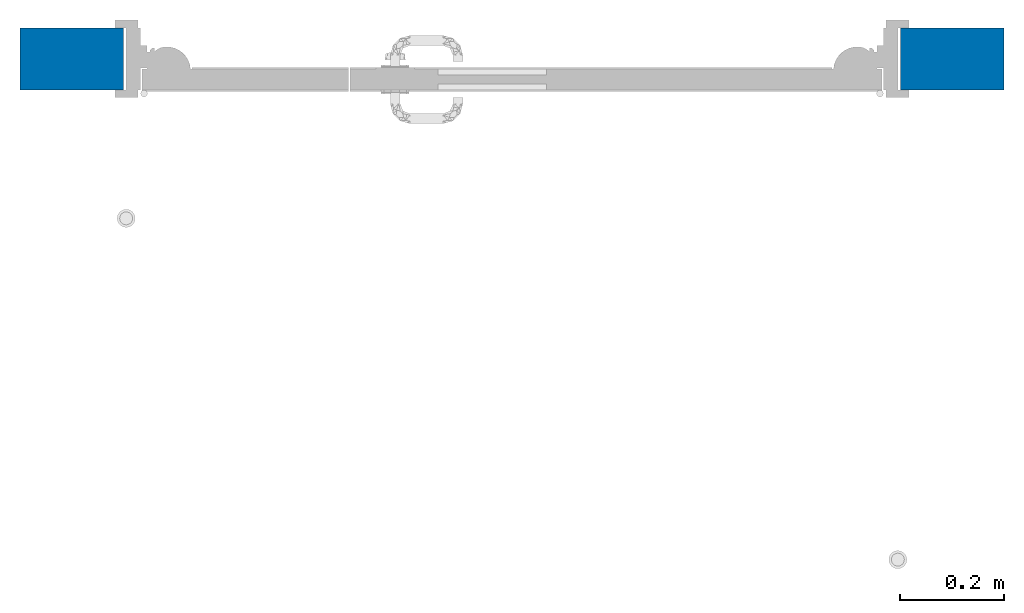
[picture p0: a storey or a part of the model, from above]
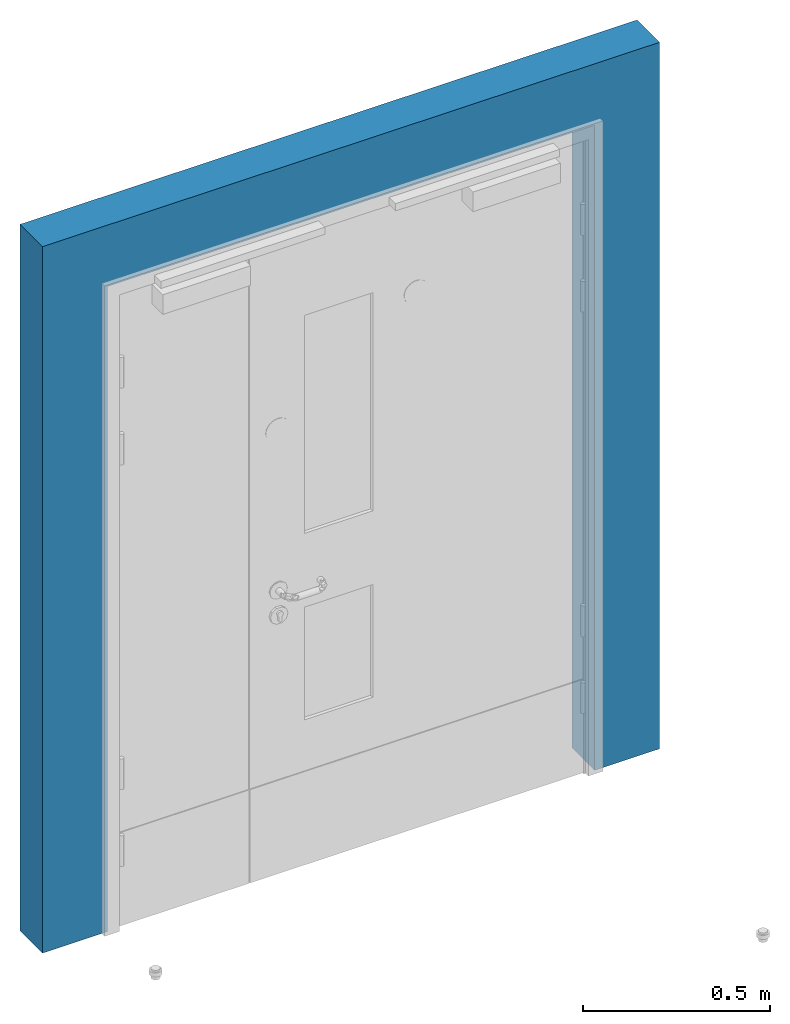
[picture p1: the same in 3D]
Properties of the parts of a building model (IFC2X3)

# File
Description: ViewDefinition [CoordinationView_V2.0]
File name: Project Number
Time: 2014-12-09T13:17:30
Written by: The EXPRESS Data Manager Version 5.01.0100.02.64mod : 6 Jun 2012
Made in: 20130709_2115(x64) - Exporter 3.12.0.0 - Alternate UI 2.12.0.0
Comment: STEP Physical File produced by: The EXPRESS Data Manager Version 5.01.0100.02.64mod : 6 Jun 2012 * Module: EDMstepFileFactory/EDMstandAlone * Creation date: Tue Dec 09 13:17:30 2014 * Host: NCL-PI08 * Database: C:\Users\KovacsG\AppData\Local\Temp\{1421A383-5437-4BC6-9070-A04BE4EB1C63}\ifc * Database version: 5507 * Database creation date: Tue Dec 09 13:17:29 2014 * Schema: IFC2X3 * Model: DataRepository.ifc * Model creation date: Tue Dec 09 13:17:29 2014 * Header model: DataRepository.ifc_HeaderModel * Header model creation date: Tue Dec 09 13:17:29 2014 * EDMuser: sdai-user * EDMgroup: sdai-group * License ID and type: 5605 : Permanent license. Expiry date: * EDMstepFileFactory options: 020000

# IfcProject, Project Number
LongName: Project Name; Phase: Project Status

# IfcSite, Default
RefLatitude: 51, 30, 0, 549316; RefLongitude: 0, -7, -34, -450321; RefElevation: 0 mm

# IfcBuildingStorey, Level 0
LongName: Level 0; Elevation: 0 mm

# IfcDoor: 1500x2100mm, NBS_AssaAbloyLtd_DrsetSym_MedicaSelectUnequalPair:1500x2100mm:411227
In: Level 0
Type - ParameterTakesPrecedence: no; Sizeable: no; Material: NBS_Concept, NBS_Glass
OverallHeight: 2100 mm; OverallWidth: 1500 mm
NBS_General - Author: NBS; BIMObjectName: NBS_AssaAbloyLtd_DoorsetSystem_MedicaSelectUnequalPair_1500x2100mm; ManufacturerURL: www.assaabloy.co.uk; NBSCertification: www.nationalbimlibrary.com/assa-abloy/h11-medica-select-unequal-pair-hardware-set; NBSDescription: Doorset system; NBSNote: 25-90-20/120 Door hardware system; NBSOfficeMasterTag: n/a; NBSReference: 25-50-20/120; NBSTypeID: n/a; ProductInformation: http://ecat.assaabloy.co.uk; Revision: n/a; Uniclass2: 25-30-20/120; Version: 2
COBie - AccessibilityPerformance: Door Opening Forces; AssetIdentifier: n/a; AssetType: Fixed; BarCode: n/a; Category: n/a; CodePerformance: CE marked for use on fire door where relevant; Color: n/a; Constituents: n/a; Description: ASSA ABLOY MEDICA SELECT unequal pair door hardware designed for use in a hospital environment.; DurationUnit: year; ExpectedLife: n/a; Features: n/a; Finish: n/a; Grade: n/a; InstallationDate: 1900-12-31T23:59:59; Manufacturer: ASSA ABLOY UK; Material: n/a; ModelNumber: Medica Select Unequal Pair; ModelReference: Medica Select Unequal Pair Hardware Set; Name: n/a; NominalHeight: 2100 mm; NominalLength: 0 mm; NominalWidth: 1500 mm; ReplacementCost: Hardware: £760.00 list price; SerialNumber: n/a; Shape: n/a; Size: 1500 x 2100 mm; SustainabilityPerformance: n/a; TagNumber: n/a; WarrantyDescription: n/a; WarrantyDurationLabor: n/a; WarrantyDurationParts: n/a; WarrantyDurationUnit: year; WarrantyGuarantorLabor: n/a; WarrantyGuarantorParts: n/a; WarrantyStartDate: 1900-12-31T23:59:59
Pset_DoorCommon - Reference: n/a; FireRating: n/a; AcousticRating: n/a; SecurityRating: n/a; IsExternal: no; Infiltration: 0 m3/s; ThermalTransmittance: 0 kg/K/s3; HandicapAccessible: yes; FireExit: no; SelfClosing: yes; SmokeStop: no; HasDrive: no
NBS_Data - AccessoryOptions: UNION J1000EE Cylinder Escutcheon; UNION J1000LT Large Turn; UNION J1000ER Indicator; ASSA ABLOY Signage; ASSA 7012F Fingerguard; ASSA Floor Socket; AdditionalHardware: ASSA ABLOY DC500A; AirTransferGrille: no; AirTransferGrilleSize: n/a; AlternativeDoorsetGlazing: n/a; AntiFingerTrapRequirement: yes; AutomaticHardware: n/a; AutomaticHardwareOptions: ASSA Smartair Access Control; UNION Codehandle; ASSA Cliq Mechatronic Cylinder Platform; BreakoutFacility: no; CloserOptions: ASSA ABLOY DC500A/DC700A Cam Motion; ASSA Floor Spring; ComponentNumber: n/a; Configuration: Leaf and part leaf, single action; CylinderOptions: ASSA P600; UNION keyULTRA Europrofile; ASSA DP; DoorNumber: n/a; DoorSeal: no; DoorsetFasteners: n/a; DoorsetType: n/a; DoorstopOptions: UNION DS101 Doorstop; Durability: 500,000 cycles; ElectronicLock: no; EmergencyPanicOperation: n/a; FloorFinish: n/a; FrameFinish: n/a; FrameMaterial: n/a; FrameProfile: n/a; FrameRevealFiller: n/a; FrameSeal: no; Furniture: n/a; GlassType: n/a; Handing: n/a; Hanging: UNION 603 BZP; HardwareSet: Medica Select Unequal Pair; HeadDetail: n/a; HingeOptions: UNION 603 BZP; HoldOpen: no; JambDetail: n/a; KeySuiting: n/a; LeafEdgings: n/a; LeafFacing: n/a; LeafSwing: n/a; LeverHandleOptions: UNION J1000 Lever Handle; UNION PH07X Pull Handle Slim; LockcaseOptions: UNION Optimus 3; UNION Flushbolt; OpeningMechanism: no; Operating: UNION J1000; OverPanels: n/a; PlatesAndStops: UNION Cylinder Escutcheon; UNION Doorstop; ASSA ABLOY Kickplate; PushPlateOptions: ASSA ABLOY Pushplate; Securing: UNION Optimus 3; UNION Key ULTRA; UNION Flushbolt; ASSA Floor Socket; SidePanels: n/a; SignageFire: n/a; SignageSecurity: n/a; SignageWayfinding: n/a; SuitableDoorsetConfiguration: Leaf and part leaf; SuitableEnvironment: Healthcare; SuitableLocation: Hospitals; SystemAccessories: ASSA Finger Guard; ThresholdBase: n/a; ThresholdRequired: no; ThresholdStripping: no; Trim: n/a; VisionPanelConfiguration: n/a

# IfcWallStandardCase: Basic Wall:Int - 120 - Brick, Basic Wall:Int - 120 - Brick:411226
In: Level 0
Type - PredefinedType: STANDARD; Material: Brick, Common 120 mm
